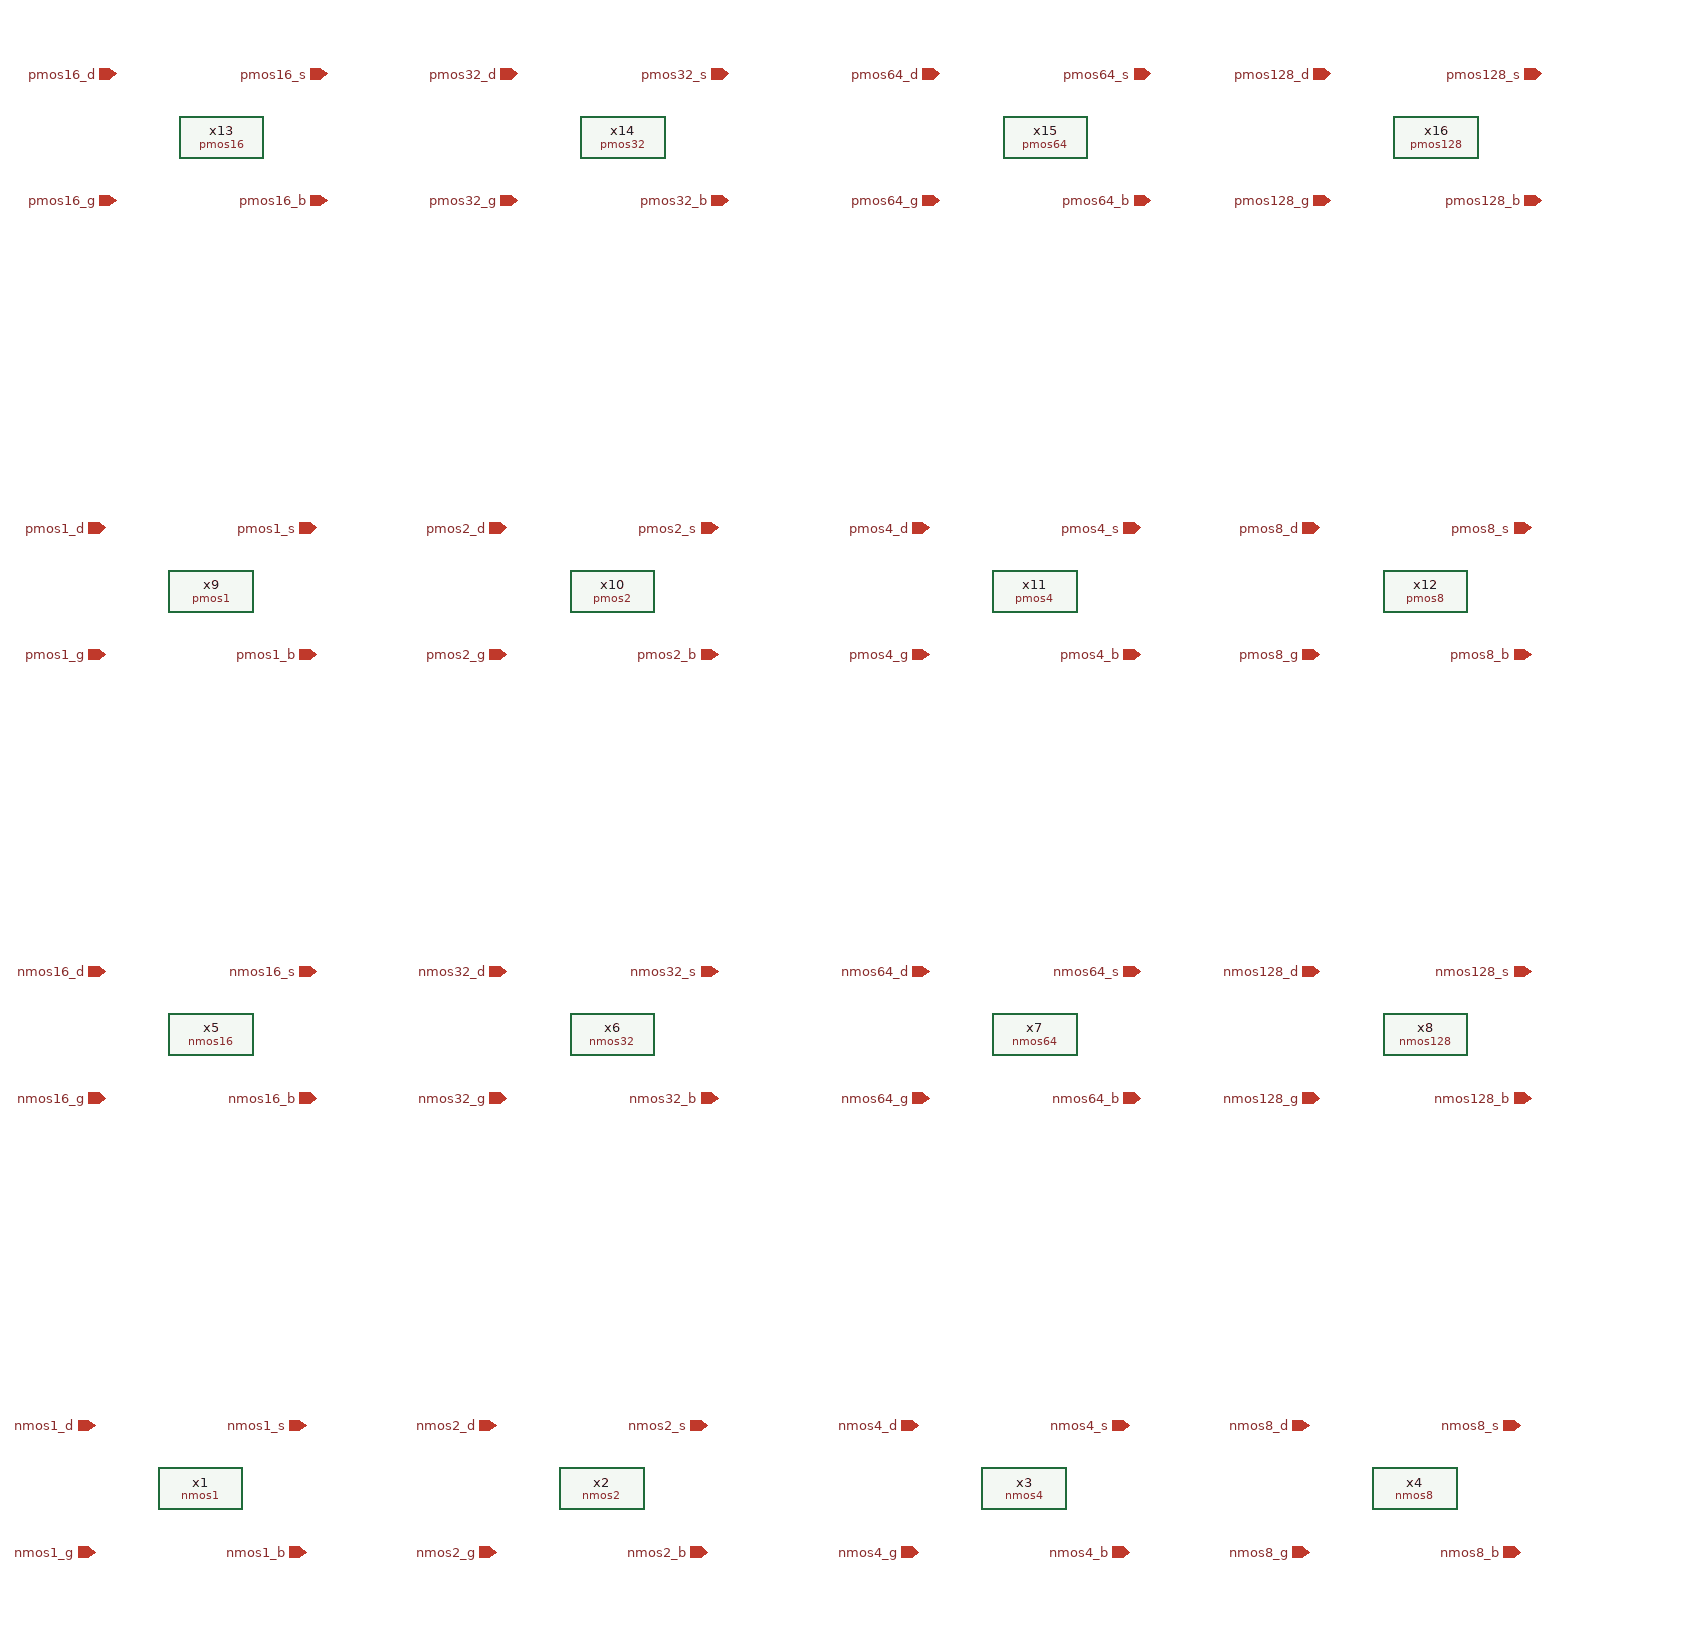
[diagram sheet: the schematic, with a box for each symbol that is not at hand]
v {xschem version=3.4.6 file_version=1.2}
G {}
K {}
V {}
S {}
E {}
C {nmos1.sym} -570 700 0 0 {name=x1}
C {devices/iopin.sym} -670 640 3 0 {name=p1 lab=nmos1_d}
C {devices/iopin.sym} -470 640 3 0 {name=p2 lab=nmos1_s}
C {devices/iopin.sym} -470 760 1 0 {name=p3 lab=nmos1_b}
C {devices/iopin.sym} -670 760 1 0 {name=p4 lab=nmos1_g}
C {devices/iopin.sym} -290 640 3 0 {name=p5 lab=nmos2_d}
C {devices/iopin.sym} -90 640 3 0 {name=p6 lab=nmos2_s}
C {devices/iopin.sym} -90 760 1 0 {name=p7 lab=nmos2_b}
C {devices/iopin.sym} -290 760 1 0 {name=p8 lab=nmos2_g}
C {nmos2.sym} -190 700 0 0 {name=x2}
C {devices/iopin.sym} 110 640 3 0 {name=p9 lab=nmos4_d}
C {devices/iopin.sym} 310 640 3 0 {name=p10 lab=nmos4_s}
C {devices/iopin.sym} 310 760 1 0 {name=p11 lab=nmos4_b}
C {devices/iopin.sym} 110 760 1 0 {name=p12 lab=nmos4_g}
C {nmos4.sym} 210 700 0 0 {name=x3}
C {devices/iopin.sym} 480 640 3 0 {name=p13 lab=nmos8_d}
C {devices/iopin.sym} 680 640 3 0 {name=p14 lab=nmos8_s}
C {devices/iopin.sym} 680 760 1 0 {name=p15 lab=nmos8_b}
C {devices/iopin.sym} 480 760 1 0 {name=p16 lab=nmos8_g}
C {nmos8.sym} 580 700 0 0 {name=x4}
C {devices/iopin.sym} -660 210 3 0 {name=p17 lab=nmos16_d}
C {devices/iopin.sym} -460 210 3 0 {name=p18 lab=nmos16_s}
C {devices/iopin.sym} -460 330 1 0 {name=p19 lab=nmos16_b}
C {devices/iopin.sym} -660 330 1 0 {name=p20 lab=nmos16_g}
C {devices/iopin.sym} -280 210 3 0 {name=p21 lab=nmos32_d}
C {devices/iopin.sym} -80 210 3 0 {name=p22 lab=nmos32_s}
C {devices/iopin.sym} -80 330 1 0 {name=p23 lab=nmos32_b}
C {devices/iopin.sym} -280 330 1 0 {name=p24 lab=nmos32_g}
C {devices/iopin.sym} 120 210 3 0 {name=p25 lab=nmos64_d}
C {devices/iopin.sym} 320 210 3 0 {name=p26 lab=nmos64_s}
C {devices/iopin.sym} 320 330 1 0 {name=p27 lab=nmos64_b}
C {devices/iopin.sym} 120 330 1 0 {name=p28 lab=nmos64_g}
C {devices/iopin.sym} 490 210 3 0 {name=p29 lab=nmos128_d}
C {devices/iopin.sym} 690 210 3 0 {name=p30 lab=nmos128_s}
C {devices/iopin.sym} 690 330 1 0 {name=p31 lab=nmos128_b}
C {devices/iopin.sym} 490 330 1 0 {name=p32 lab=nmos128_g}
C {nmos16.sym} -560 270 0 0 {name=x5}
C {nmos32.sym} -180 270 0 0 {name=x6}
C {nmos64.sym} 220 270 0 0 {name=x7}
C {nmos128.sym} 590 270 0 0 {name=x8}
C {pmos1.sym} -560 -150 0 0 {name=x9}
C {devices/iopin.sym} -660 -210 3 0 {name=p33 lab=pmos1_d}
C {devices/iopin.sym} -460 -210 3 0 {name=p34 lab=pmos1_s}
C {devices/iopin.sym} -460 -90 1 0 {name=p35 lab=pmos1_b}
C {devices/iopin.sym} -660 -90 1 0 {name=p36 lab=pmos1_g}
C {devices/iopin.sym} -280 -210 3 0 {name=p37 lab=pmos2_d}
C {devices/iopin.sym} -80 -210 3 0 {name=p38 lab=pmos2_s}
C {devices/iopin.sym} -80 -90 1 0 {name=p39 lab=pmos2_b}
C {devices/iopin.sym} -280 -90 1 0 {name=p40 lab=pmos2_g}
C {pmos2.sym} -180 -150 0 0 {name=x10}
C {devices/iopin.sym} 120 -210 3 0 {name=p41 lab=pmos4_d}
C {devices/iopin.sym} 320 -210 3 0 {name=p42 lab=pmos4_s}
C {devices/iopin.sym} 320 -90 1 0 {name=p43 lab=pmos4_b}
C {devices/iopin.sym} 120 -90 1 0 {name=p44 lab=pmos4_g}
C {pmos4.sym} 220 -150 0 0 {name=x11}
C {devices/iopin.sym} 490 -210 3 0 {name=p45 lab=pmos8_d}
C {devices/iopin.sym} 690 -210 3 0 {name=p46 lab=pmos8_s}
C {devices/iopin.sym} 690 -90 1 0 {name=p47 lab=pmos8_b}
C {devices/iopin.sym} 490 -90 1 0 {name=p48 lab=pmos8_g}
C {pmos8.sym} 590 -150 0 0 {name=x12}
C {devices/iopin.sym} -650 -640 3 0 {name=p49 lab=pmos16_d}
C {devices/iopin.sym} -450 -640 3 0 {name=p50 lab=pmos16_s}
C {devices/iopin.sym} -450 -520 1 0 {name=p51 lab=pmos16_b}
C {devices/iopin.sym} -650 -520 1 0 {name=p52 lab=pmos16_g}
C {devices/iopin.sym} -270 -640 3 0 {name=p53 lab=pmos32_d}
C {devices/iopin.sym} -70 -640 3 0 {name=p54 lab=pmos32_s}
C {devices/iopin.sym} -70 -520 1 0 {name=p55 lab=pmos32_b}
C {devices/iopin.sym} -270 -520 1 0 {name=p56 lab=pmos32_g}
C {devices/iopin.sym} 130 -640 3 0 {name=p57 lab=pmos64_d}
C {devices/iopin.sym} 330 -640 3 0 {name=p58 lab=pmos64_s}
C {devices/iopin.sym} 330 -520 1 0 {name=p59 lab=pmos64_b}
C {devices/iopin.sym} 130 -520 1 0 {name=p60 lab=pmos64_g}
C {devices/iopin.sym} 500 -640 3 0 {name=p61 lab=pmos128_d}
C {devices/iopin.sym} 700 -640 3 0 {name=p62 lab=pmos128_s}
C {devices/iopin.sym} 700 -520 1 0 {name=p63 lab=pmos128_b}
C {devices/iopin.sym} 500 -520 1 0 {name=p64 lab=pmos128_g}
C {pmos16.sym} -550 -580 0 0 {name=x13}
C {pmos32.sym} -170 -580 0 0 {name=x14}
C {pmos64.sym} 230 -580 0 0 {name=x15}
C {pmos128.sym} 600 -580 0 0 {name=x16}
